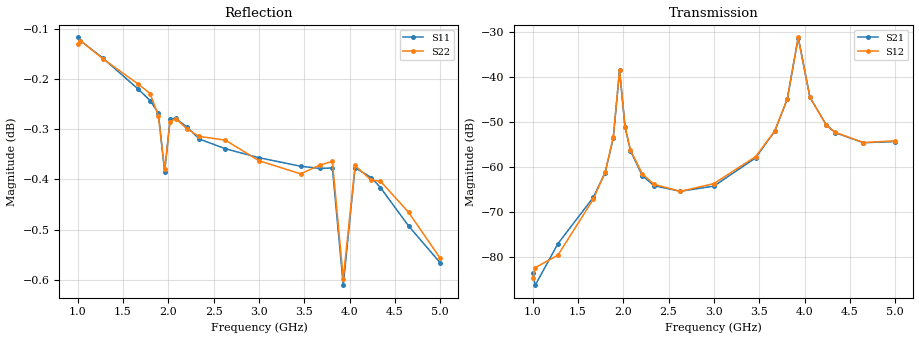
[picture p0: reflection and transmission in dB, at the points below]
!Keysight Technologies,N5242A,MY48420869,A.10.65.01
!Date: Friday, September 13, 2019 11:45:47
!Correction: S33(Full 4 Port(1,2,3,4))
!S43(Full 4 Port(1,2,3,4))
!S34(Full 4 Port(1,2,3,4))
!S44(Full 4 Port(1,2,3,4))
!S2P File: Measurements: S33, S43, S34, S44:
!Created with skrf (http://scikit-rf.org).
# Hz S RI R 50.0
!freq ReS11 ImS11 ReS21 ImS21 ReS12 ImS12 ReS22 ImS22
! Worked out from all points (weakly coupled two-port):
!   401 points, 1 GHz to 5 GHz, reference 50 ohm
!   highest |S21| = -31.18 dB at 3.93 GHz (marker M1); lowest = -86.3 dB at 1.03 GHz (marker M2)
!   lowest |S11| = -0.6 dB at 3.93 GHz (marker M3), VSWR 28.44, Z = 11.6 - j118 ohm
!   |S11| at or under -10 dB: nowhere
!   |S22| runs from -0.6 to -0.1 dB; largest |S21 - S12| = 0.00022
!   S11 on the Smith chart (normalised r, x): 1 GHz: 0.01, -0.70; 1.8 GHz: 0.01, +0.11; 2.63 GHz: 0.04, +1.06; 3.46 GHz: 15, +22; 4.24 GHz: 0.06, -1.22; 5 GHz: 0.03, -0.16
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1e9  -0.3427 -0.9252  6.45e-05 -1.49e-05  5.72e-05 -7.67e-06  -0.3589 -0.9174
1.03e9  -0.3925 -0.9044  4.39e-05 -1.99e-05  7.26e-05 -2.06e-05  -0.4111 -0.8961
1.28e9  -0.7465 -0.6379  0.000108 -8.83e-05  6.44e-05 -8.15e-05  -0.7569 -0.6253
1.67e9  -0.9748 -0.0176  -5.57e-05 -0.000454  -2.69e-05 -0.000436  -0.976 -0.0132
1.8e9  -0.9512 0.2021  -0.000262 -0.000819  -0.000278 -0.000822  -0.9528 0.2021
1.89e9  -0.9064 0.3445  -0.00113 -0.00176  -0.00115 -0.0018  -0.9067 0.342
1.96e9  -0.8477 0.4433  -0.0106 0.00544  -0.0107 0.00544  -0.8513 0.4376
2.02e9  -0.8093 0.5318  0.00104 0.0026  0.00104 0.00262  -0.8135 0.5241
2.08e9  -0.7497 0.6131  0.000817 0.00128  0.000854 0.00129  -0.7557 0.6056
2.21e9  -0.5944 0.7621  0.000611 0.000519  0.000642 0.000538  -0.6066 0.7519
2.34e9  -0.4114 0.8717  0.000556 0.00027  0.000568 0.000295  -0.4312 0.8627
2.63e9  0.0525 0.9603  0.000535 1.9e-05  0.000534 1.74e-05  0.0158 0.9635
3e9  0.6148 0.737  0.00046 -0.000403  0.000506 -0.000411  0.5773 0.7659
3.46e9  0.9561 0.0584  3.75e-05 -0.00126  5.98e-05 -0.0013  0.9501 0.1079
3.67e9  0.9075 -0.3051  -0.00095 -0.0023  -0.000974 -0.00231  0.9228 -0.2578
3.81e9  0.7987 -0.5281  -0.00397 -0.00409  -0.00399 -0.00414  0.8234 -0.4915
3.93e9  0.6512 -0.6669  -0.0177 0.0212  -0.0178 0.0213  0.6805 -0.639
4.06e9  0.4876 -0.8241  0.00443 0.00397  0.00444 0.00395  0.5179 -0.806
4.24e9  0.185 -0.9373  0.00285 0.000767  0.00281 0.000744  0.206 -0.9323
4.34e9  0.00232 -0.9532  0.0024 0.000113  0.00243 0.000104  0.0192 -0.9544
4.65e9  -0.5218 -0.7877  0.00158 -0.000984  0.00157 -0.00101  -0.5231 -0.7904
5e9  -0.8899 -0.2929  0.000507 -0.00185  0.000533 -0.00188  -0.8964 -0.2757
